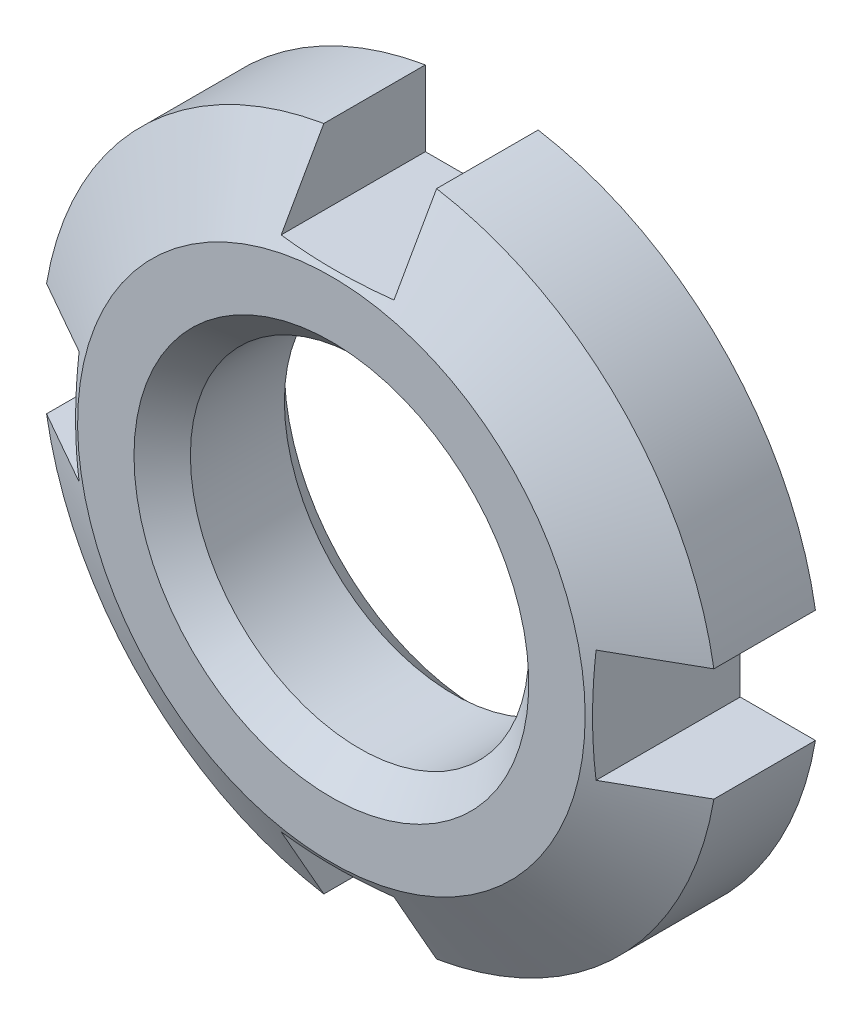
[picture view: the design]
ISO-10303-21;
HEADER;
FILE_DESCRIPTION(('STEP AP214'),'2;1');
FILE_NAME('part.step','',(''),(''),'','','');
FILE_SCHEMA(('AUTOMOTIVE_DESIGN { 1 0 10303 214 1 1 1 1 }'));
ENDSEC;
DATA;
#1=APPLICATION_CONTEXT('core data for automotive mechanical design processes');
#2=APPLICATION_PROTOCOL_DEFINITION('international standard','automotive_design',2000,#1);
#3=PRODUCT_CONTEXT('',#1,'mechanical');
#4=PRODUCT('Part','Part','',(#3));
#5=PRODUCT_RELATED_PRODUCT_CATEGORY('part','',(#4));
#6=PRODUCT_DEFINITION_FORMATION('','',#4);
#7=PRODUCT_DEFINITION_CONTEXT('part definition',#1,'design');
#8=PRODUCT_DEFINITION('design','',#6,#7);
#9=PRODUCT_DEFINITION_SHAPE('','',#8);
#10=(LENGTH_UNIT() NAMED_UNIT(*) SI_UNIT(.MILLI.,.METRE.));
#11=(NAMED_UNIT(*) PLANE_ANGLE_UNIT() SI_UNIT($,.RADIAN.));
#12=(NAMED_UNIT(*) SI_UNIT($,.STERADIAN.) SOLID_ANGLE_UNIT());
#13=UNCERTAINTY_MEASURE_WITH_UNIT(LENGTH_MEASURE(1.E-05),#10,'distance_accuracy_value','');
#14=(GEOMETRIC_REPRESENTATION_CONTEXT(3) GLOBAL_UNCERTAINTY_ASSIGNED_CONTEXT((#13)) GLOBAL_UNIT_ASSIGNED_CONTEXT((#10,
#11,#12)) REPRESENTATION_CONTEXT('',''));
#15=CARTESIAN_POINT('',(0.,0.,0.));
#16=DIRECTION('',(0.,0.,1.));
#17=DIRECTION('',(1.,0.,0.));
#18=AXIS2_PLACEMENT_3D('',#15,#16,#17);
#19=CARTESIAN_POINT('',(-9.,0.,0.));
#20=DIRECTION('',(0.,0.,1.));
#21=DIRECTION('',(1.,0.,0.));
#22=AXIS2_PLACEMENT_3D('',#19,#20,#21);
#23=PLANE('',#22);
#24=CARTESIAN_POINT('',(0.,0.,0.));
#25=DIRECTION('',(0.,0.,1.));
#26=DIRECTION('',(1.,0.,0.));
#27=AXIS2_PLACEMENT_3D('',#24,#25,#26);
#28=CIRCLE('',#27,5.25);
#29=CARTESIAN_POINT('',(5.25,0.,0.));
#30=VERTEX_POINT('',#29);
#31=EDGE_CURVE('E275',#30,#30,#28,.T.);
#32=ORIENTED_EDGE('',*,*,#31,.T.);
#33=EDGE_LOOP('',(#32));
#34=FACE_BOUND('',#33,.T.);
#35=DIRECTION('',(1.,0.,0.));
#36=VECTOR('',#35,1.);
#37=CARTESIAN_POINT('',(-9.87411967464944,-1.4999999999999,0.));
#38=LINE('',#37,#36);
#39=CARTESIAN_POINT('',(-8.87411967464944,-1.49999999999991,0.));
#40=VERTEX_POINT('',#39);
#41=CARTESIAN_POINT('',(-6.87411967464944,-1.49999999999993,0.));
#42=VERTEX_POINT('',#41);
#43=EDGE_CURVE('E539',#40,#42,#38,.T.);
#44=ORIENTED_EDGE('',*,*,#43,.T.);
#45=DIRECTION('',(0.,1.,0.));
#46=VECTOR('',#45,1.);
#47=CARTESIAN_POINT('',(-6.87411967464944,-1.49999999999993,0.));
#48=LINE('',#47,#46);
#49=CARTESIAN_POINT('',(-6.87411967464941,1.50000000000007,0.));
#50=VERTEX_POINT('',#49);
#51=EDGE_CURVE('E165',#42,#50,#48,.T.);
#52=ORIENTED_EDGE('',*,*,#51,.T.);
#53=DIRECTION('',(-1.,0.,0.));
#54=VECTOR('',#53,1.);
#55=CARTESIAN_POINT('',(-9.87411967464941,1.5000000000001,0.));
#56=LINE('',#55,#54);
#57=CARTESIAN_POINT('',(-8.87411967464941,1.50000000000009,0.));
#58=VERTEX_POINT('',#57);
#59=EDGE_CURVE('E151',#50,#58,#56,.T.);
#60=ORIENTED_EDGE('',*,*,#59,.T.);
#61=CARTESIAN_POINT('',(0.,0.,0.));
#62=DIRECTION('',(0.,0.,1.));
#63=DIRECTION('',(1.,0.,0.));
#64=AXIS2_PLACEMENT_3D('',#61,#62,#63);
#65=CIRCLE('',#64,9.);
#66=CARTESIAN_POINT('',(-1.5,8.87411967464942,0.));
#67=VERTEX_POINT('',#66);
#68=EDGE_CURVE('E164',#67,#58,#65,.T.);
#69=ORIENTED_EDGE('',*,*,#68,.F.);
#70=DIRECTION('',(0.,-1.,0.));
#71=VECTOR('',#70,1.);
#72=CARTESIAN_POINT('',(-1.5,9.87411967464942,0.));
#73=LINE('',#72,#71);
#74=CARTESIAN_POINT('',(-1.5,6.87411967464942,0.));
#75=VERTEX_POINT('',#74);
#76=EDGE_CURVE('E213',#67,#75,#73,.T.);
#77=ORIENTED_EDGE('',*,*,#76,.T.);
#78=DIRECTION('',(1.,0.,0.));
#79=VECTOR('',#78,1.);
#80=CARTESIAN_POINT('',(-1.5,6.87411967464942,0.));
#81=LINE('',#80,#79);
#82=CARTESIAN_POINT('',(1.5,6.87411967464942,0.));
#83=VERTEX_POINT('',#82);
#84=EDGE_CURVE('E210',#75,#83,#81,.T.);
#85=ORIENTED_EDGE('',*,*,#84,.T.);
#86=DIRECTION('',(0.,1.,0.));
#87=VECTOR('',#86,1.);
#88=CARTESIAN_POINT('',(1.5,9.87411967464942,0.));
#89=LINE('',#88,#87);
#90=CARTESIAN_POINT('',(1.5,8.87411967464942,0.));
#91=VERTEX_POINT('',#90);
#92=EDGE_CURVE('E207',#83,#91,#89,.T.);
#93=ORIENTED_EDGE('',*,*,#92,.T.);
#94=CARTESIAN_POINT('',(8.87411967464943,1.49999999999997,0.));
#95=VERTEX_POINT('',#94);
#96=EDGE_CURVE('E174',#95,#91,#65,.T.);
#97=ORIENTED_EDGE('',*,*,#96,.F.);
#98=DIRECTION('',(-1.,0.,0.));
#99=VECTOR('',#98,1.);
#100=CARTESIAN_POINT('',(9.87411967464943,1.49999999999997,0.));
#101=LINE('',#100,#99);
#102=CARTESIAN_POINT('',(6.87411967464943,1.49999999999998,0.));
#103=VERTEX_POINT('',#102);
#104=EDGE_CURVE('E215',#95,#103,#101,.T.);
#105=ORIENTED_EDGE('',*,*,#104,.T.);
#106=DIRECTION('',(0.,-1.,0.));
#107=VECTOR('',#106,1.);
#108=CARTESIAN_POINT('',(6.87411967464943,1.49999999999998,0.));
#109=LINE('',#108,#107);
#110=CARTESIAN_POINT('',(6.87411967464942,-1.50000000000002,0.));
#111=VERTEX_POINT('',#110);
#112=EDGE_CURVE('E251',#103,#111,#109,.T.);
#113=ORIENTED_EDGE('',*,*,#112,.T.);
#114=DIRECTION('',(1.,0.,0.));
#115=VECTOR('',#114,1.);
#116=CARTESIAN_POINT('',(9.87411967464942,-1.50000000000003,0.));
#117=LINE('',#116,#115);
#118=CARTESIAN_POINT('',(8.87411967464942,-1.50000000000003,0.));
#119=VERTEX_POINT('',#118);
#120=EDGE_CURVE('E581',#111,#119,#117,.T.);
#121=ORIENTED_EDGE('',*,*,#120,.T.);
#122=CARTESIAN_POINT('',(1.49999999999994,-8.87411967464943,0.));
#123=VERTEX_POINT('',#122);
#124=EDGE_CURVE('E178',#123,#119,#65,.T.);
#125=ORIENTED_EDGE('',*,*,#124,.F.);
#126=DIRECTION('',(0.,1.,0.));
#127=VECTOR('',#126,1.);
#128=CARTESIAN_POINT('',(1.49999999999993,-9.87411967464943,0.));
#129=LINE('',#128,#127);
#130=CARTESIAN_POINT('',(1.49999999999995,-6.87411967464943,0.));
#131=VERTEX_POINT('',#130);
#132=EDGE_CURVE('E573',#123,#131,#129,.T.);
#133=ORIENTED_EDGE('',*,*,#132,.T.);
#134=DIRECTION('',(-1.,0.,0.));
#135=VECTOR('',#134,1.);
#136=CARTESIAN_POINT('',(1.49999999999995,-6.87411967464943,0.));
#137=LINE('',#136,#135);
#138=CARTESIAN_POINT('',(-1.50000000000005,-6.87411967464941,0.));
#139=VERTEX_POINT('',#138);
#140=EDGE_CURVE('E591',#131,#139,#137,.T.);
#141=ORIENTED_EDGE('',*,*,#140,.T.);
#142=DIRECTION('',(0.,-1.,0.));
#143=VECTOR('',#142,1.);
#144=CARTESIAN_POINT('',(-1.50000000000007,-9.87411967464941,0.));
#145=LINE('',#144,#143);
#146=CARTESIAN_POINT('',(-1.50000000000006,-8.87411967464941,0.));
#147=VERTEX_POINT('',#146);
#148=EDGE_CURVE('E546',#139,#147,#145,.T.);
#149=ORIENTED_EDGE('',*,*,#148,.T.);
#150=EDGE_CURVE('E172',#40,#147,#65,.T.);
#151=ORIENTED_EDGE('',*,*,#150,.F.);
#152=EDGE_LOOP('',(#44,#52,#60,#69,#77,#85,#93,#97,#105,#113,#121,#125,#133,#141,#149,#151));
#153=FACE_BOUND('',#152,.T.);
#154=ADVANCED_FACE('F34',(#34,#153),#23,.F.);
#155=CARTESIAN_POINT('',(-6.75,0.,4.));
#156=DIRECTION('',(0.,0.,-1.));
#157=DIRECTION('',(-1.,0.,0.));
#158=AXIS2_PLACEMENT_3D('',#155,#156,#157);
#159=PLANE('',#158);
#160=CARTESIAN_POINT('',(0.,0.,4.));
#161=DIRECTION('',(0.,0.,-1.));
#162=DIRECTION('',(-1.,0.,0.));
#163=AXIS2_PLACEMENT_3D('',#160,#161,#162);
#164=CIRCLE('',#163,5.25);
#165=CARTESIAN_POINT('',(-5.25,0.,4.));
#166=VERTEX_POINT('',#165);
#167=EDGE_CURVE('E11',#166,#166,#164,.T.);
#168=ORIENTED_EDGE('',*,*,#167,.T.);
#169=EDGE_LOOP('',(#168));
#170=FACE_BOUND('',#169,.T.);
#171=CARTESIAN_POINT('',(0.,0.,4.));
#172=DIRECTION('',(0.,0.,1.));
#173=DIRECTION('',(1.,0.,0.));
#174=AXIS2_PLACEMENT_3D('',#171,#172,#173);
#175=CIRCLE('',#174,6.75);
#176=CARTESIAN_POINT('',(6.75,0.,4.));
#177=VERTEX_POINT('',#176);
#178=EDGE_CURVE('E192',#177,#177,#175,.T.);
#179=ORIENTED_EDGE('',*,*,#178,.T.);
#180=EDGE_LOOP('',(#179));
#181=FACE_BOUND('',#180,.T.);
#182=ADVANCED_FACE('F300',(#170,#181),#159,.F.);
#183=CARTESIAN_POINT('',(0.,0.,0.));
#184=DIRECTION('',(0.,0.,1.));
#185=DIRECTION('',(1.,0.,0.));
#186=AXIS2_PLACEMENT_3D('',#183,#184,#185);
#187=CYLINDRICAL_SURFACE('',#186,9.);
#188=DIRECTION('',(0.,0.,1.));
#189=VECTOR('',#188,1.);
#190=CARTESIAN_POINT('',(-8.87411967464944,-1.49999999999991,0.));
#191=LINE('',#190,#189);
#192=CARTESIAN_POINT('',(-8.87411967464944,-1.49999999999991,2.70096189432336));
#193=VERTEX_POINT('',#192);
#194=EDGE_CURVE('E540',#40,#193,#191,.T.);
#195=ORIENTED_EDGE('',*,*,#194,.F.);
#196=ORIENTED_EDGE('',*,*,#150,.T.);
#197=DIRECTION('',(0.,0.,1.));
#198=VECTOR('',#197,1.);
#199=CARTESIAN_POINT('',(-1.50000000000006,-8.87411967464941,0.));
#200=LINE('',#199,#198);
#201=CARTESIAN_POINT('',(-1.50000000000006,-8.87411967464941,2.70096189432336));
#202=VERTEX_POINT('',#201);
#203=EDGE_CURVE('E543',#202,#147,#200,.F.);
#204=ORIENTED_EDGE('',*,*,#203,.F.);
#205=CARTESIAN_POINT('',(0.,0.,2.70096189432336));
#206=DIRECTION('',(0.,0.,1.));
#207=DIRECTION('',(1.,0.,0.));
#208=AXIS2_PLACEMENT_3D('',#205,#206,#207);
#209=CIRCLE('',#208,9.);
#210=EDGE_CURVE('E186',#193,#202,#209,.T.);
#211=ORIENTED_EDGE('',*,*,#210,.F.);
#212=EDGE_LOOP('',(#195,#196,#204,#211));
#213=FACE_BOUND('',#212,.T.);
#214=ADVANCED_FACE('F302',(#213),#187,.T.);
#215=DIRECTION('',(0.,0.,1.));
#216=VECTOR('',#215,1.);
#217=CARTESIAN_POINT('',(-8.87411967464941,1.50000000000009,0.));
#218=LINE('',#217,#216);
#219=CARTESIAN_POINT('',(-8.87411967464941,1.50000000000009,2.70096189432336));
#220=VERTEX_POINT('',#219);
#221=EDGE_CURVE('E148',#220,#58,#218,.F.);
#222=ORIENTED_EDGE('',*,*,#221,.F.);
#223=CARTESIAN_POINT('',(-1.5,8.87411967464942,2.70096189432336));
#224=VERTEX_POINT('',#223);
#225=EDGE_CURVE('E180',#224,#220,#209,.T.);
#226=ORIENTED_EDGE('',*,*,#225,.F.);
#227=DIRECTION('',(0.,0.,1.));
#228=VECTOR('',#227,1.);
#229=CARTESIAN_POINT('',(-1.5,8.87411967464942,0.));
#230=LINE('',#229,#228);
#231=EDGE_CURVE('E170',#67,#224,#230,.T.);
#232=ORIENTED_EDGE('',*,*,#231,.F.);
#233=ORIENTED_EDGE('',*,*,#68,.T.);
#234=EDGE_LOOP('',(#222,#226,#232,#233));
#235=FACE_BOUND('',#234,.T.);
#236=ADVANCED_FACE('F169',(#235),#187,.T.);
#237=CARTESIAN_POINT('',(0.,0.,2.70096189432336));
#238=DIRECTION('',(0.,0.,-1.));
#239=DIRECTION('',(-1.,0.,0.));
#240=AXIS2_PLACEMENT_3D('',#237,#238,#239);
#241=CONICAL_SURFACE('',#240,9.,1.0471975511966);
#242=ORIENTED_EDGE('',*,*,#178,.F.);
#243=EDGE_LOOP('',(#242));
#244=FACE_BOUND('',#243,.T.);
#245=CARTESIAN_POINT('',(-12.0482242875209,-1.49999999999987,0.887366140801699));
#246=CARTESIAN_POINT('',(-11.6966393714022,-1.49999999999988,1.08879188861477));
#247=CARTESIAN_POINT('',(-11.345001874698,-1.49999999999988,1.29012601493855));
#248=CARTESIAN_POINT('',(-10.6415746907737,-1.49999999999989,1.69252518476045));
#249=CARTESIAN_POINT('',(-10.2897850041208,-1.49999999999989,1.89359022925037));
#250=CARTESIAN_POINT('',(-9.58601538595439,-1.4999999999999,2.29536027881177));
#251=CARTESIAN_POINT('',(-9.23403546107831,-1.4999999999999,2.49606529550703));
#252=CARTESIAN_POINT('',(-8.52979354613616,-1.49999999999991,2.89698358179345));
#253=CARTESIAN_POINT('',(-8.17753155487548,-1.49999999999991,3.09719684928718));
#254=CARTESIAN_POINT('',(-7.47258606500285,-1.49999999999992,3.49691980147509));
#255=CARTESIAN_POINT('',(-7.11990254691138,-1.49999999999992,3.69642945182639));
#256=CARTESIAN_POINT('',(-6.41393090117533,-1.49999999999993,4.09436975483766));
#257=CARTESIAN_POINT('',(-6.06064277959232,-1.49999999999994,4.29280041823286));
#258=CARTESIAN_POINT('',(-5.52995961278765,-1.49999999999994,4.58912088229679));
#259=CARTESIAN_POINT('',(-5.35293605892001,-1.49999999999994,4.68767565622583));
#260=CARTESIAN_POINT('',(-4.99855912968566,-1.49999999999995,4.88418867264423));
#261=CARTESIAN_POINT('',(-4.82120575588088,-1.49999999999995,4.98214691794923));
#262=CARTESIAN_POINT('',(-4.4660556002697,-1.49999999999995,5.17727253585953));
#263=CARTESIAN_POINT('',(-4.28825880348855,-1.49999999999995,5.27443988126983));
#264=CARTESIAN_POINT('',(-3.93203557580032,-1.49999999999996,5.46761959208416));
#265=CARTESIAN_POINT('',(-3.75360913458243,-1.49999999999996,5.56363193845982));
#266=CARTESIAN_POINT('',(-3.5747746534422,-1.49999999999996,5.65888482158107));
#267=B_SPLINE_CURVE_WITH_KNOTS('',3,(#245,#246,#247,#248,#249,#250,#251,#252,#253,#254,#255,
#256,#257,#258,#259,#260,#261,#262,#263,#264,#265,#266),.UNSPECIFIED.,.F.,.F.,(4,2,2,2,2,2,2,2,
2,2,4),(0.,1.21558990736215,2.4311753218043,3.64672075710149,4.86227136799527,6.07788050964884,
7.29347753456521,7.90130346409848,8.50912652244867,9.11697039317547,9.72482426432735),.UNSPECIFIED.);
#268=CARTESIAN_POINT('',(-6.87411967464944,-1.49999999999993,3.8349506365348));
#269=VERTEX_POINT('',#268);
#270=EDGE_CURVE('E532',#193,#269,#267,.T.);
#271=ORIENTED_EDGE('',*,*,#270,.F.);
#272=ORIENTED_EDGE('',*,*,#210,.T.);
#273=CARTESIAN_POINT('',(-1.50000000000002,-3.57477465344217,5.65888482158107));
#274=CARTESIAN_POINT('',(-1.50000000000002,-3.72761749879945,5.57748838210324));
#275=CARTESIAN_POINT('',(-1.50000000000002,-3.88015653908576,5.49552547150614));
#276=CARTESIAN_POINT('',(-1.50000000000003,-4.18475291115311,5.33071348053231));
#277=CARTESIAN_POINT('',(-1.50000000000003,-4.3368102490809,5.24786441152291));
#278=CARTESIAN_POINT('',(-1.50000000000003,-4.64056875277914,5.08152711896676));
#279=CARTESIAN_POINT('',(-1.50000000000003,-4.7922699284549,4.99803891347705));
#280=CARTESIAN_POINT('',(-1.50000000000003,-5.09539871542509,4.83056622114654));
#281=CARTESIAN_POINT('',(-1.50000000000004,-5.24682632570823,4.74658173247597));
#282=CARTESIAN_POINT('',(-1.50000000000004,-5.70077797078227,4.49406380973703));
#283=CARTESIAN_POINT('',(-1.50000000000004,-6.00298389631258,4.32495873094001));
#284=CARTESIAN_POINT('',(-1.50000000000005,-6.60685200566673,3.98577781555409));
#285=CARTESIAN_POINT('',(-1.50000000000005,-6.90851418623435,3.815701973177));
#286=CARTESIAN_POINT('',(-1.50000000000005,-7.31254193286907,3.58732547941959));
#287=CARTESIAN_POINT('',(-1.50000000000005,-7.41507371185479,3.52931868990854));
#288=CARTESIAN_POINT('',(-1.50000000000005,-7.62009847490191,3.41323585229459));
#289=CARTESIAN_POINT('',(-1.50000000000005,-7.72259145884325,3.3551598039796));
#290=CARTESIAN_POINT('',(-1.50000000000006,-8.17753998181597,3.09719293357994));
#291=CARTESIAN_POINT('',(-1.50000000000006,-8.5298098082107,2.89697457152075));
#292=CARTESIAN_POINT('',(-1.50000000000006,-9.2340693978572,2.49604572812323));
#293=CARTESIAN_POINT('',(-1.50000000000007,-9.58605916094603,2.29533524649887));
#294=CARTESIAN_POINT('',(-1.50000000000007,-10.2898305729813,1.89356425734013));
#295=CARTESIAN_POINT('',(-1.50000000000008,-10.6416122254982,1.6925037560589));
#296=CARTESIAN_POINT('',(-1.50000000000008,-11.3450215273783,1.29011472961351));
#297=CARTESIAN_POINT('',(-1.50000000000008,-11.6966491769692,1.08878620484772));
#298=CARTESIAN_POINT('',(-1.50000000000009,-12.0482242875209,0.887366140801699));
#299=B_SPLINE_CURVE_WITH_KNOTS('',3,(#273,#274,#275,#276,#277,#278,#279,#280,#281,#282,#283,
#284,#285,#286,#287,#288,#289,#290,#291,#292,#293,#294,#295,#296,#297,#298),.UNSPECIFIED.,.F.,
.F.,(4,2,2,2,2,2,2,2,2,2,2,2,4),(0.,0.519492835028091,1.03897901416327,1.55845057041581,
2.07792404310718,3.11682622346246,4.15573460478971,4.50914367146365,4.86255382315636,
6.07813233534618,7.29371155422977,8.509269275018,9.72482519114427),.UNSPECIFIED.);
#300=CARTESIAN_POINT('',(-1.50000000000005,-6.87411967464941,3.8349506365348));
#301=VERTEX_POINT('',#300);
#302=EDGE_CURVE('E551',#301,#202,#299,.T.);
#303=ORIENTED_EDGE('',*,*,#302,.F.);
#304=CARTESIAN_POINT('',(6.55885978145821,-6.87411967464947,2.41161333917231));
#305=CARTESIAN_POINT('',(6.33984463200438,-6.87411967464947,2.49887607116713));
#306=CARTESIAN_POINT('',(6.12004253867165,-6.87411967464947,2.58421702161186));
#307=CARTESIAN_POINT('',(5.67875239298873,-6.87411967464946,2.75015745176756));
#308=CARTESIAN_POINT('',(5.45726499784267,-6.87411967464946,2.83075868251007));
#309=CARTESIAN_POINT('',(5.01119995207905,-6.87411967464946,2.98678307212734));
#310=CARTESIAN_POINT('',(4.78661232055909,-6.87411967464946,3.06217785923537));
#311=CARTESIAN_POINT('',(4.33513790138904,-6.87411967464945,3.20628899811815));
#312=CARTESIAN_POINT('',(4.10824976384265,-6.87411967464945,3.27500114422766));
#313=CARTESIAN_POINT('',(3.65628850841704,-6.87411967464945,3.40326846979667));
#314=CARTESIAN_POINT('',(3.43125606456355,-6.87411967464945,3.46296603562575));
#315=CARTESIAN_POINT('',(2.97894419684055,-6.87411967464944,3.57331853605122));
#316=CARTESIAN_POINT('',(2.75166457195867,-6.87411967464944,3.62397265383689));
#317=CARTESIAN_POINT('',(2.29520223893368,-6.87411967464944,3.71478537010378));
#318=CARTESIAN_POINT('',(2.06602132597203,-6.87411967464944,3.75495291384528));
#319=CARTESIAN_POINT('',(1.60593171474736,-6.87411967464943,3.82349163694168));
#320=CARTESIAN_POINT('',(1.3750234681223,-6.87411967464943,3.85186579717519));
#321=CARTESIAN_POINT('',(0.986468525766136,-6.87411967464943,3.88868115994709));
#322=CARTESIAN_POINT('',(0.829145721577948,-6.87411967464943,3.9005982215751));
#323=CARTESIAN_POINT('',(0.514158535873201,-6.87411967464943,3.91828190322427));
#324=CARTESIAN_POINT('',(0.356494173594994,-6.87411967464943,3.92404886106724));
#325=CARTESIAN_POINT('',(0.0410198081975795,-6.87411967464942,3.92931284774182));
#326=CARTESIAN_POINT('',(-0.116790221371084,-6.87411967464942,3.92880831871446));
#327=CARTESIAN_POINT('',(-0.432259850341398,-6.87411967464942,3.92154340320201));
#328=CARTESIAN_POINT('',(-0.589919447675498,-6.87411967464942,3.91478293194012));
#329=CARTESIAN_POINT('',(-1.06354657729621,-6.87411967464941,3.88521008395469));
#330=CARTESIAN_POINT('',(-1.37897450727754,-6.87411967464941,3.85308764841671));
#331=CARTESIAN_POINT('',(-2.00660335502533,-6.87411967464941,3.76646010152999));
#332=CARTESIAN_POINT('',(-2.31880439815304,-6.87411967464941,3.71195586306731));
#333=CARTESIAN_POINT('',(-3.17085179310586,-6.8741196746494,3.53625507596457));
#334=CARTESIAN_POINT('',(-3.70669852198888,-6.8741196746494,3.39564334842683));
#335=CARTESIAN_POINT('',(-4.50141537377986,-6.87411967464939,3.15491392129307));
#336=CARTESIAN_POINT('',(-4.76507173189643,-6.87411967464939,3.06960166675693));
#337=CARTESIAN_POINT('',(-5.28961720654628,-6.87411967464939,2.89082717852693));
#338=CARTESIAN_POINT('',(-5.55050650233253,-6.87411967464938,2.797365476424));
#339=CARTESIAN_POINT('',(-6.06847952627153,-6.87411967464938,2.60431902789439));
#340=CARTESIAN_POINT('',(-6.32557583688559,-6.87411967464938,2.50476769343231));
#341=CARTESIAN_POINT('',(-6.83763997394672,-6.87411967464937,2.30030968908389));
#342=CARTESIAN_POINT('',(-7.09260769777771,-6.87411967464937,2.19540276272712));
#343=CARTESIAN_POINT('',(-7.5995555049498,-6.87411967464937,1.98168702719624));
#344=CARTESIAN_POINT('',(-7.85154384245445,-6.87411967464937,1.87289771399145));
#345=CARTESIAN_POINT('',(-8.35388494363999,-6.87411967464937,1.65172066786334));
#346=CARTESIAN_POINT('',(-8.60423798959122,-6.87411967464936,1.53933357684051));
#347=CARTESIAN_POINT('',(-8.85391912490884,-6.87411967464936,1.42549923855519));
#348=B_SPLINE_CURVE_WITH_KNOTS('',3,(#304,#305,#306,#307,#308,#309,#310,#311,#312,#313,#314,
#315,#316,#317,#318,#319,#320,#321,#322,#323,#324,#325,#326,#327,#328,#329,#330,#331,#332,#333,
#334,#335,#336,#337,#338,#339,#340,#341,#342,#343,#344,#345,#346,#347),.UNSPECIFIED.,.F.,.F.,(4,
2,2,2,2,2,2,2,2,2,2,2,2,2,2,2,2,2,2,2,2,4),(0.,0.707298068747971,1.41433317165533,
2.12495849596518,2.83602819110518,3.5343173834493,4.23266961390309,4.93042417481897,
5.62800226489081,6.10121365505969,6.57439905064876,7.04770198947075,7.52101134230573,
8.47118428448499,9.42132017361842,11.0805690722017,11.9118610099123,12.7430987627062,
13.5701261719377,14.3971932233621,15.2205703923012,16.0438014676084),.UNSPECIFIED.);
#349=CARTESIAN_POINT('',(1.49999999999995,-6.87411967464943,3.8349506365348));
#350=VERTEX_POINT('',#349);
#351=EDGE_CURVE('E57',#350,#301,#348,.T.);
#352=ORIENTED_EDGE('',*,*,#351,.F.);
#353=CARTESIAN_POINT('',(1.49999999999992,-12.0482242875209,0.887366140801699));
#354=CARTESIAN_POINT('',(1.49999999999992,-11.6966393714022,1.08879188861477));
#355=CARTESIAN_POINT('',(1.49999999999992,-11.345001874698,1.29012601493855));
#356=CARTESIAN_POINT('',(1.49999999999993,-10.6415746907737,1.69252518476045));
#357=CARTESIAN_POINT('',(1.49999999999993,-10.2897850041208,1.89359022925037));
#358=CARTESIAN_POINT('',(1.49999999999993,-9.58601538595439,2.29536027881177));
#359=CARTESIAN_POINT('',(1.49999999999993,-9.2340354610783,2.49606529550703));
#360=CARTESIAN_POINT('',(1.49999999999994,-8.52979354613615,2.89698358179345));
#361=CARTESIAN_POINT('',(1.49999999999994,-8.17753155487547,3.09719684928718));
#362=CARTESIAN_POINT('',(1.49999999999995,-7.47258606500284,3.49691980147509));
#363=CARTESIAN_POINT('',(1.49999999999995,-7.11990254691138,3.69642945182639));
#364=CARTESIAN_POINT('',(1.49999999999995,-6.41393090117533,4.09436975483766));
#365=CARTESIAN_POINT('',(1.49999999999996,-6.06064277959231,4.29280041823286));
#366=CARTESIAN_POINT('',(1.49999999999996,-5.52995961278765,4.58912088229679));
#367=CARTESIAN_POINT('',(1.49999999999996,-5.35293605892,4.68767565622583));
#368=CARTESIAN_POINT('',(1.49999999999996,-4.99855912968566,4.88418867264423));
#369=CARTESIAN_POINT('',(1.49999999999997,-4.82120575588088,4.98214691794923));
#370=CARTESIAN_POINT('',(1.49999999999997,-4.46605560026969,5.17727253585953));
#371=CARTESIAN_POINT('',(1.49999999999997,-4.28825880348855,5.27443988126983));
#372=CARTESIAN_POINT('',(1.49999999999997,-3.93203557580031,5.46761959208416));
#373=CARTESIAN_POINT('',(1.49999999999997,-3.75360913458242,5.56363193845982));
#374=CARTESIAN_POINT('',(1.49999999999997,-3.5747746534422,5.65888482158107));
#375=B_SPLINE_CURVE_WITH_KNOTS('',3,(#353,#354,#355,#356,#357,#358,#359,#360,#361,#362,#363,
#364,#365,#366,#367,#368,#369,#370,#371,#372,#373,#374),.UNSPECIFIED.,.F.,.F.,(4,2,2,2,2,2,2,2,
2,2,4),(0.,1.21558990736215,2.4311753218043,3.64672075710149,4.86227136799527,6.07788050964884,
7.29347753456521,7.90130346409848,8.50912652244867,9.11697039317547,9.72482426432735),.UNSPECIFIED.);
#376=CARTESIAN_POINT('',(1.49999999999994,-8.87411967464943,2.70096189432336));
#377=VERTEX_POINT('',#376);
#378=EDGE_CURVE('E566',#377,#350,#375,.T.);
#379=ORIENTED_EDGE('',*,*,#378,.F.);
#380=CARTESIAN_POINT('',(8.87411967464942,-1.50000000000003,2.70096189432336));
#381=VERTEX_POINT('',#380);
#382=EDGE_CURVE('E190',#377,#381,#209,.T.);
#383=ORIENTED_EDGE('',*,*,#382,.T.);
#384=CARTESIAN_POINT('',(3.57477465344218,-1.50000000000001,5.65888482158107));
#385=CARTESIAN_POINT('',(3.72761749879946,-1.50000000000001,5.57748838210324));
#386=CARTESIAN_POINT('',(3.88015653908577,-1.50000000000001,5.49552547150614));
#387=CARTESIAN_POINT('',(4.18475291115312,-1.50000000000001,5.33071348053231));
#388=CARTESIAN_POINT('',(4.33681024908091,-1.50000000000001,5.24786441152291));
#389=CARTESIAN_POINT('',(4.64056875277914,-1.50000000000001,5.08152711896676));
#390=CARTESIAN_POINT('',(4.7922699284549,-1.50000000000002,4.99803891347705));
#391=CARTESIAN_POINT('',(5.0953987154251,-1.50000000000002,4.83056622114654));
#392=CARTESIAN_POINT('',(5.24682632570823,-1.50000000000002,4.74658173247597));
#393=CARTESIAN_POINT('',(5.70077797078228,-1.50000000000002,4.49406380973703));
#394=CARTESIAN_POINT('',(6.00298389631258,-1.50000000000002,4.32495873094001));
#395=CARTESIAN_POINT('',(6.60685200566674,-1.50000000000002,3.98577781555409));
#396=CARTESIAN_POINT('',(6.90851418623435,-1.50000000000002,3.815701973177));
#397=CARTESIAN_POINT('',(7.31254193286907,-1.50000000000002,3.58732547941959));
#398=CARTESIAN_POINT('',(7.41507371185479,-1.50000000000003,3.52931868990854));
#399=CARTESIAN_POINT('',(7.62009847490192,-1.50000000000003,3.41323585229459));
#400=CARTESIAN_POINT('',(7.72259145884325,-1.50000000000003,3.3551598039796));
#401=CARTESIAN_POINT('',(8.17753998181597,-1.50000000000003,3.09719293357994));
#402=CARTESIAN_POINT('',(8.5298098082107,-1.50000000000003,2.89697457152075));
#403=CARTESIAN_POINT('',(9.23406939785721,-1.50000000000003,2.49604572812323));
#404=CARTESIAN_POINT('',(9.58605916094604,-1.50000000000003,2.29533524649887));
#405=CARTESIAN_POINT('',(10.2898305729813,-1.50000000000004,1.89356425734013));
#406=CARTESIAN_POINT('',(10.6416122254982,-1.50000000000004,1.6925037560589));
#407=CARTESIAN_POINT('',(11.3450215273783,-1.50000000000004,1.29011472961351));
#408=CARTESIAN_POINT('',(11.6966491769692,-1.50000000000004,1.08878620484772));
#409=CARTESIAN_POINT('',(12.0482242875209,-1.50000000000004,0.887366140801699));
#410=B_SPLINE_CURVE_WITH_KNOTS('',3,(#384,#385,#386,#387,#388,#389,#390,#391,#392,#393,#394,
#395,#396,#397,#398,#399,#400,#401,#402,#403,#404,#405,#406,#407,#408,#409),.UNSPECIFIED.,.F.,
.F.,(4,2,2,2,2,2,2,2,2,2,2,2,4),(0.,0.519492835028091,1.03897901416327,1.55845057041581,
2.07792404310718,3.11682622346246,4.15573460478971,4.50914367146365,4.86255382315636,
6.07813233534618,7.29371155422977,8.509269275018,9.72482519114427),.UNSPECIFIED.);
#411=CARTESIAN_POINT('',(6.87411967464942,-1.50000000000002,3.8349506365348));
#412=VERTEX_POINT('',#411);
#413=EDGE_CURVE('E252',#412,#381,#410,.T.);
#414=ORIENTED_EDGE('',*,*,#413,.F.);
#415=CARTESIAN_POINT('',(6.87411967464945,6.55885978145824,2.41161333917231));
#416=CARTESIAN_POINT('',(6.87411967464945,6.3398446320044,2.49887607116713));
#417=CARTESIAN_POINT('',(6.87411967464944,6.12004253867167,2.58421702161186));
#418=CARTESIAN_POINT('',(6.87411967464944,5.67875239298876,2.75015745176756));
#419=CARTESIAN_POINT('',(6.87411967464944,5.4572649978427,2.83075868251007));
#420=CARTESIAN_POINT('',(6.87411967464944,5.01119995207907,2.98678307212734));
#421=CARTESIAN_POINT('',(6.87411967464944,4.78661232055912,3.06217785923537));
#422=CARTESIAN_POINT('',(6.87411967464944,4.33513790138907,3.20628899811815));
#423=CARTESIAN_POINT('',(6.87411967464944,4.10824976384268,3.27500114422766));
#424=CARTESIAN_POINT('',(6.87411967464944,3.65628850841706,3.40326846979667));
#425=CARTESIAN_POINT('',(6.87411967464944,3.43125606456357,3.46296603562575));
#426=CARTESIAN_POINT('',(6.87411967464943,2.97894419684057,3.57331853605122));
#427=CARTESIAN_POINT('',(6.87411967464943,2.75166457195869,3.62397265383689));
#428=CARTESIAN_POINT('',(6.87411967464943,2.2952022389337,3.71478537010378));
#429=CARTESIAN_POINT('',(6.87411967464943,2.06602132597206,3.75495291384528));
#430=CARTESIAN_POINT('',(6.87411967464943,1.60593171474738,3.82349163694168));
#431=CARTESIAN_POINT('',(6.87411967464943,1.37502346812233,3.85186579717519));
#432=CARTESIAN_POINT('',(6.87411967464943,0.98646852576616,3.88868115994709));
#433=CARTESIAN_POINT('',(6.87411967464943,0.829145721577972,3.9005982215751));
#434=CARTESIAN_POINT('',(6.87411967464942,0.514158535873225,3.91828190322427));
#435=CARTESIAN_POINT('',(6.87411967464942,0.356494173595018,3.92404886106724));
#436=CARTESIAN_POINT('',(6.87411967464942,0.0410198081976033,3.92931284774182));
#437=CARTESIAN_POINT('',(6.87411967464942,-0.11679022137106,3.92880831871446));
#438=CARTESIAN_POINT('',(6.87411967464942,-0.432259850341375,3.92154340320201));
#439=CARTESIAN_POINT('',(6.87411967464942,-0.589919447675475,3.91478293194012));
#440=CARTESIAN_POINT('',(6.87411967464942,-1.06354657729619,3.88521008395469));
#441=CARTESIAN_POINT('',(6.87411967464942,-1.37897450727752,3.85308764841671));
#442=CARTESIAN_POINT('',(6.87411967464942,-2.00660335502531,3.76646010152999));
#443=CARTESIAN_POINT('',(6.87411967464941,-2.31880439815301,3.71195586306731));
#444=CARTESIAN_POINT('',(6.87411967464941,-3.17085179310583,3.53625507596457));
#445=CARTESIAN_POINT('',(6.87411967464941,-3.70669852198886,3.39564334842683));
#446=CARTESIAN_POINT('',(6.87411967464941,-4.50141537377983,3.15491392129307));
#447=CARTESIAN_POINT('',(6.87411967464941,-4.76507173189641,3.06960166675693));
#448=CARTESIAN_POINT('',(6.8741196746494,-5.28961720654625,2.89082717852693));
#449=CARTESIAN_POINT('',(6.8741196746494,-5.5505065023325,2.797365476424));
#450=CARTESIAN_POINT('',(6.8741196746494,-6.06847952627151,2.60431902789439));
#451=CARTESIAN_POINT('',(6.8741196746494,-6.32557583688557,2.50476769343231));
#452=CARTESIAN_POINT('',(6.8741196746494,-6.83763997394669,2.30030968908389));
#453=CARTESIAN_POINT('',(6.8741196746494,-7.09260769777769,2.19540276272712));
#454=CARTESIAN_POINT('',(6.8741196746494,-7.59955550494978,1.98168702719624));
#455=CARTESIAN_POINT('',(6.8741196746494,-7.85154384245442,1.87289771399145));
#456=CARTESIAN_POINT('',(6.87411967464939,-8.35388494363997,1.65172066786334));
#457=CARTESIAN_POINT('',(6.87411967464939,-8.6042379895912,1.53933357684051));
#458=CARTESIAN_POINT('',(6.87411967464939,-8.85391912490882,1.42549923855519));
#459=B_SPLINE_CURVE_WITH_KNOTS('',3,(#415,#416,#417,#418,#419,#420,#421,#422,#423,#424,#425,
#426,#427,#428,#429,#430,#431,#432,#433,#434,#435,#436,#437,#438,#439,#440,#441,#442,#443,#444,
#445,#446,#447,#448,#449,#450,#451,#452,#453,#454,#455,#456,#457,#458),.UNSPECIFIED.,.F.,.F.,(4,
2,2,2,2,2,2,2,2,2,2,2,2,2,2,2,2,2,2,2,2,4),(0.,0.707298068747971,1.41433317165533,
2.12495849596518,2.83602819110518,3.5343173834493,4.23266961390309,4.93042417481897,
5.62800226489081,6.10121365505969,6.57439905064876,7.04770198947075,7.52101134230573,
8.47118428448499,9.42132017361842,11.0805690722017,11.9118610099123,12.7430987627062,
13.5701261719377,14.3971932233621,15.2205703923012,16.0438014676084),.UNSPECIFIED.);
#460=CARTESIAN_POINT('',(6.87411967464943,1.49999999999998,3.8349506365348));
#461=VERTEX_POINT('',#460);
#462=EDGE_CURVE('E245',#461,#412,#459,.T.);
#463=ORIENTED_EDGE('',*,*,#462,.F.);
#464=CARTESIAN_POINT('',(12.0482242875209,1.49999999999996,0.887366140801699));
#465=CARTESIAN_POINT('',(11.6966393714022,1.49999999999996,1.08879188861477));
#466=CARTESIAN_POINT('',(11.345001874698,1.49999999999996,1.29012601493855));
#467=CARTESIAN_POINT('',(10.6415746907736,1.49999999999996,1.69252518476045));
#468=CARTESIAN_POINT('',(10.2897850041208,1.49999999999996,1.89359022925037));
#469=CARTESIAN_POINT('',(9.58601538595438,1.49999999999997,2.29536027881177));
#470=CARTESIAN_POINT('',(9.2340354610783,1.49999999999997,2.49606529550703));
#471=CARTESIAN_POINT('',(8.52979354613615,1.49999999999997,2.89698358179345));
#472=CARTESIAN_POINT('',(8.17753155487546,1.49999999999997,3.09719684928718));
#473=CARTESIAN_POINT('',(7.47258606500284,1.49999999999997,3.49691980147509));
#474=CARTESIAN_POINT('',(7.11990254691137,1.49999999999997,3.69642945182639));
#475=CARTESIAN_POINT('',(6.41393090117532,1.49999999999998,4.09436975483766));
#476=CARTESIAN_POINT('',(6.06064277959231,1.49999999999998,4.29280041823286));
#477=CARTESIAN_POINT('',(5.52995961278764,1.49999999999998,4.58912088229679));
#478=CARTESIAN_POINT('',(5.35293605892,1.49999999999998,4.68767565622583));
#479=CARTESIAN_POINT('',(4.99855912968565,1.49999999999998,4.88418867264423));
#480=CARTESIAN_POINT('',(4.82120575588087,1.49999999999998,4.98214691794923));
#481=CARTESIAN_POINT('',(4.46605560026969,1.49999999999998,5.17727253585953));
#482=CARTESIAN_POINT('',(4.28825880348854,1.49999999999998,5.27443988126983));
#483=CARTESIAN_POINT('',(3.93203557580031,1.49999999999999,5.46761959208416));
#484=CARTESIAN_POINT('',(3.75360913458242,1.49999999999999,5.56363193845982));
#485=CARTESIAN_POINT('',(3.57477465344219,1.49999999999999,5.65888482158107));
#486=B_SPLINE_CURVE_WITH_KNOTS('',3,(#464,#465,#466,#467,#468,#469,#470,#471,#472,#473,#474,
#475,#476,#477,#478,#479,#480,#481,#482,#483,#484,#485),.UNSPECIFIED.,.F.,.F.,(4,2,2,2,2,2,2,2,
2,2,4),(0.,1.21558990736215,2.4311753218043,3.64672075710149,4.86227136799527,6.07788050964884,
7.29347753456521,7.90130346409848,8.50912652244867,9.11697039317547,9.72482426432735),.UNSPECIFIED.);
#487=CARTESIAN_POINT('',(8.87411967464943,1.49999999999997,2.70096189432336));
#488=VERTEX_POINT('',#487);
#489=EDGE_CURVE('E218',#488,#461,#486,.T.);
#490=ORIENTED_EDGE('',*,*,#489,.F.);
#491=CARTESIAN_POINT('',(1.5,8.87411967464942,2.70096189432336));
#492=VERTEX_POINT('',#491);
#493=EDGE_CURVE('E187',#488,#492,#209,.T.);
#494=ORIENTED_EDGE('',*,*,#493,.T.);
#495=CARTESIAN_POINT('',(1.5,3.57477465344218,5.65888482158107));
#496=CARTESIAN_POINT('',(1.5,3.72761749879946,5.57748838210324));
#497=CARTESIAN_POINT('',(1.5,3.88015653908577,5.49552547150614));
#498=CARTESIAN_POINT('',(1.5,4.18475291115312,5.33071348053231));
#499=CARTESIAN_POINT('',(1.5,4.33681024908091,5.24786441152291));
#500=CARTESIAN_POINT('',(1.5,4.64056875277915,5.08152711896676));
#501=CARTESIAN_POINT('',(1.5,4.79226992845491,4.99803891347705));
#502=CARTESIAN_POINT('',(1.5,5.0953987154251,4.83056622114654));
#503=CARTESIAN_POINT('',(1.5,5.24682632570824,4.74658173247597));
#504=CARTESIAN_POINT('',(1.5,5.70077797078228,4.49406380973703));
#505=CARTESIAN_POINT('',(1.5,6.00298389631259,4.32495873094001));
#506=CARTESIAN_POINT('',(1.5,6.60685200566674,3.98577781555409));
#507=CARTESIAN_POINT('',(1.5,6.90851418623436,3.815701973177));
#508=CARTESIAN_POINT('',(1.5,7.31254193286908,3.58732547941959));
#509=CARTESIAN_POINT('',(1.5,7.4150737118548,3.52931868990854));
#510=CARTESIAN_POINT('',(1.5,7.62009847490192,3.41323585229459));
#511=CARTESIAN_POINT('',(1.5,7.72259145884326,3.3551598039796));
#512=CARTESIAN_POINT('',(1.5,8.17753998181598,3.09719293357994));
#513=CARTESIAN_POINT('',(1.5,8.52980980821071,2.89697457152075));
#514=CARTESIAN_POINT('',(1.5,9.23406939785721,2.49604572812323));
#515=CARTESIAN_POINT('',(1.5,9.58605916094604,2.29533524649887));
#516=CARTESIAN_POINT('',(1.5,10.2898305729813,1.89356425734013));
#517=CARTESIAN_POINT('',(1.5,10.6416122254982,1.6925037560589));
#518=CARTESIAN_POINT('',(1.5,11.3450215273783,1.29011472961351));
#519=CARTESIAN_POINT('',(1.5,11.6966491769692,1.08878620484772));
#520=CARTESIAN_POINT('',(1.5,12.0482242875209,0.887366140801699));
#521=B_SPLINE_CURVE_WITH_KNOTS('',3,(#495,#496,#497,#498,#499,#500,#501,#502,#503,#504,#505,
#506,#507,#508,#509,#510,#511,#512,#513,#514,#515,#516,#517,#518,#519,#520),.UNSPECIFIED.,.F.,
.F.,(4,2,2,2,2,2,2,2,2,2,2,2,4),(0.,0.519492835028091,1.03897901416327,1.55845057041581,
2.07792404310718,3.11682622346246,4.15573460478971,4.50914367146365,4.86255382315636,
6.07813233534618,7.29371155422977,8.509269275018,9.72482519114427),.UNSPECIFIED.);
#522=CARTESIAN_POINT('',(1.5,6.87411967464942,3.8349506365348));
#523=VERTEX_POINT('',#522);
#524=EDGE_CURVE('E171',#523,#492,#521,.T.);
#525=ORIENTED_EDGE('',*,*,#524,.F.);
#526=CARTESIAN_POINT('',(-6.55885978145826,6.87411967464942,2.41161333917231));
#527=CARTESIAN_POINT('',(-6.33984463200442,6.87411967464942,2.49887607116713));
#528=CARTESIAN_POINT('',(-6.1200425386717,6.87411967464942,2.58421702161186));
#529=CARTESIAN_POINT('',(-5.67875239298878,6.87411967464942,2.75015745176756));
#530=CARTESIAN_POINT('',(-5.45726499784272,6.87411967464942,2.83075868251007));
#531=CARTESIAN_POINT('',(-5.0111999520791,6.87411967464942,2.98678307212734));
#532=CARTESIAN_POINT('',(-4.78661232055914,6.87411967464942,3.06217785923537));
#533=CARTESIAN_POINT('',(-4.33513790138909,6.87411967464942,3.20628899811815));
#534=CARTESIAN_POINT('',(-4.1082497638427,6.87411967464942,3.27500114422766));
#535=CARTESIAN_POINT('',(-3.65628850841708,6.87411967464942,3.40326846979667));
#536=CARTESIAN_POINT('',(-3.43125606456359,6.87411967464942,3.46296603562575));
#537=CARTESIAN_POINT('',(-2.97894419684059,6.87411967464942,3.57331853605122));
#538=CARTESIAN_POINT('',(-2.75166457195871,6.87411967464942,3.62397265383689));
#539=CARTESIAN_POINT('',(-2.29520223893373,6.87411967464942,3.71478537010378));
#540=CARTESIAN_POINT('',(-2.06602132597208,6.87411967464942,3.75495291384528));
#541=CARTESIAN_POINT('',(-1.60593171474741,6.87411967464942,3.82349163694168));
#542=CARTESIAN_POINT('',(-1.37502346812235,6.87411967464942,3.85186579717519));
#543=CARTESIAN_POINT('',(-0.986468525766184,6.87411967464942,3.88868115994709));
#544=CARTESIAN_POINT('',(-0.829145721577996,6.87411967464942,3.9005982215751));
#545=CARTESIAN_POINT('',(-0.514158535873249,6.87411967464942,3.91828190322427));
#546=CARTESIAN_POINT('',(-0.356494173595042,6.87411967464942,3.92404886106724));
#547=CARTESIAN_POINT('',(-0.0410198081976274,6.87411967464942,3.92931284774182));
#548=CARTESIAN_POINT('',(0.116790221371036,6.87411967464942,3.92880831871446));
#549=CARTESIAN_POINT('',(0.432259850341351,6.87411967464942,3.92154340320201));
#550=CARTESIAN_POINT('',(0.589919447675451,6.87411967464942,3.91478293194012));
#551=CARTESIAN_POINT('',(1.06354657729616,6.87411967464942,3.88521008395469));
#552=CARTESIAN_POINT('',(1.37897450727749,6.87411967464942,3.85308764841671));
#553=CARTESIAN_POINT('',(2.00660335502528,6.87411967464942,3.76646010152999));
#554=CARTESIAN_POINT('',(2.31880439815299,6.87411967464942,3.71195586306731));
#555=CARTESIAN_POINT('',(3.17085179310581,6.87411967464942,3.53625507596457));
#556=CARTESIAN_POINT('',(3.70669852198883,6.87411967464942,3.39564334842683));
#557=CARTESIAN_POINT('',(4.50141537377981,6.87411967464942,3.15491392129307));
#558=CARTESIAN_POINT('',(4.76507173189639,6.87411967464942,3.06960166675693));
#559=CARTESIAN_POINT('',(5.28961720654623,6.87411967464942,2.89082717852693));
#560=CARTESIAN_POINT('',(5.55050650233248,6.87411967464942,2.797365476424));
#561=CARTESIAN_POINT('',(6.06847952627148,6.87411967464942,2.60431902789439));
#562=CARTESIAN_POINT('',(6.32557583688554,6.87411967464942,2.50476769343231));
#563=CARTESIAN_POINT('',(6.83763997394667,6.87411967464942,2.30030968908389));
#564=CARTESIAN_POINT('',(7.09260769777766,6.87411967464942,2.19540276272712));
#565=CARTESIAN_POINT('',(7.59955550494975,6.87411967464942,1.98168702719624));
#566=CARTESIAN_POINT('',(7.8515438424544,6.87411967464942,1.87289771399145));
#567=CARTESIAN_POINT('',(8.35388494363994,6.87411967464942,1.65172066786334));
#568=CARTESIAN_POINT('',(8.60423798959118,6.87411967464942,1.53933357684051));
#569=CARTESIAN_POINT('',(8.85391912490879,6.87411967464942,1.42549923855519));
#570=B_SPLINE_CURVE_WITH_KNOTS('',3,(#526,#527,#528,#529,#530,#531,#532,#533,#534,#535,#536,
#537,#538,#539,#540,#541,#542,#543,#544,#545,#546,#547,#548,#549,#550,#551,#552,#553,#554,#555,
#556,#557,#558,#559,#560,#561,#562,#563,#564,#565,#566,#567,#568,#569),.UNSPECIFIED.,.F.,.F.,(4,
2,2,2,2,2,2,2,2,2,2,2,2,2,2,2,2,2,2,2,2,4),(0.,0.70729806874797,1.41433317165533,
2.12495849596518,2.83602819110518,3.5343173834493,4.23266961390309,4.93042417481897,
5.62800226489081,6.10121365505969,6.57439905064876,7.04770198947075,7.52101134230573,
8.47118428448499,9.42132017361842,11.0805690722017,11.9118610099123,12.7430987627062,
13.5701261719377,14.3971932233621,15.2205703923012,16.0438014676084),.UNSPECIFIED.);
#571=CARTESIAN_POINT('',(-1.5,6.87411967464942,3.8349506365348));
#572=VERTEX_POINT('',#571);
#573=EDGE_CURVE('E176',#572,#523,#570,.T.);
#574=ORIENTED_EDGE('',*,*,#573,.F.);
#575=CARTESIAN_POINT('',(-1.5,12.0482242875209,0.887366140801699));
#576=CARTESIAN_POINT('',(-1.5,11.6966393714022,1.08879188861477));
#577=CARTESIAN_POINT('',(-1.5,11.345001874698,1.29012601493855));
#578=CARTESIAN_POINT('',(-1.5,10.6415746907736,1.69252518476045));
#579=CARTESIAN_POINT('',(-1.5,10.2897850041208,1.89359022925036));
#580=CARTESIAN_POINT('',(-1.5,9.58601538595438,2.29536027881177));
#581=CARTESIAN_POINT('',(-1.5,9.2340354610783,2.49606529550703));
#582=CARTESIAN_POINT('',(-1.5,8.52979354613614,2.89698358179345));
#583=CARTESIAN_POINT('',(-1.5,8.17753155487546,3.09719684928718));
#584=CARTESIAN_POINT('',(-1.5,7.47258606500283,3.49691980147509));
#585=CARTESIAN_POINT('',(-1.5,7.11990254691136,3.69642945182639));
#586=CARTESIAN_POINT('',(-1.5,6.41393090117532,4.09436975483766));
#587=CARTESIAN_POINT('',(-1.5,6.0606427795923,4.29280041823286));
#588=CARTESIAN_POINT('',(-1.5,5.52995961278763,4.58912088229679));
#589=CARTESIAN_POINT('',(-1.5,5.35293605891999,4.68767565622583));
#590=CARTESIAN_POINT('',(-1.5,4.99855912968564,4.88418867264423));
#591=CARTESIAN_POINT('',(-1.5,4.82120575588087,4.98214691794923));
#592=CARTESIAN_POINT('',(-1.5,4.46605560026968,5.17727253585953));
#593=CARTESIAN_POINT('',(-1.5,4.28825880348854,5.27443988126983));
#594=CARTESIAN_POINT('',(-1.5,3.9320355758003,5.46761959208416));
#595=CARTESIAN_POINT('',(-1.5,3.75360913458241,5.56363193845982));
#596=CARTESIAN_POINT('',(-1.5,3.57477465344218,5.65888482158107));
#597=B_SPLINE_CURVE_WITH_KNOTS('',3,(#575,#576,#577,#578,#579,#580,#581,#582,#583,#584,#585,
#586,#587,#588,#589,#590,#591,#592,#593,#594,#595,#596),.UNSPECIFIED.,.F.,.F.,(4,2,2,2,2,2,2,2,
2,2,4),(0.,1.21558990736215,2.4311753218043,3.64672075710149,4.86227136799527,6.07788050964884,
7.29347753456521,7.90130346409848,8.50912652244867,9.11697039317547,9.72482426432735),.UNSPECIFIED.);
#598=EDGE_CURVE('E273',#224,#572,#597,.T.);
#599=ORIENTED_EDGE('',*,*,#598,.F.);
#600=ORIENTED_EDGE('',*,*,#225,.T.);
#601=CARTESIAN_POINT('',(-3.57477465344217,1.50000000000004,5.65888482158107));
#602=CARTESIAN_POINT('',(-3.72761749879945,1.50000000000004,5.57748838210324));
#603=CARTESIAN_POINT('',(-3.88015653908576,1.50000000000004,5.49552547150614));
#604=CARTESIAN_POINT('',(-4.18475291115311,1.50000000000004,5.33071348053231));
#605=CARTESIAN_POINT('',(-4.3368102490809,1.50000000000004,5.24786441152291));
#606=CARTESIAN_POINT('',(-4.64056875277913,1.50000000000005,5.08152711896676));
#607=CARTESIAN_POINT('',(-4.79226992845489,1.50000000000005,4.99803891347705));
#608=CARTESIAN_POINT('',(-5.09539871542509,1.50000000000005,4.83056622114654));
#609=CARTESIAN_POINT('',(-5.24682632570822,1.50000000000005,4.74658173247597));
#610=CARTESIAN_POINT('',(-5.70077797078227,1.50000000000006,4.49406380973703));
#611=CARTESIAN_POINT('',(-6.00298389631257,1.50000000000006,4.32495873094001));
#612=CARTESIAN_POINT('',(-6.60685200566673,1.50000000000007,3.98577781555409));
#613=CARTESIAN_POINT('',(-6.90851418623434,1.50000000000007,3.815701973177));
#614=CARTESIAN_POINT('',(-7.31254193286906,1.50000000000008,3.58732547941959));
#615=CARTESIAN_POINT('',(-7.41507371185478,1.50000000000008,3.52931868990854));
#616=CARTESIAN_POINT('',(-7.62009847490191,1.50000000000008,3.41323585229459));
#617=CARTESIAN_POINT('',(-7.72259145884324,1.50000000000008,3.3551598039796));
#618=CARTESIAN_POINT('',(-8.17753998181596,1.50000000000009,3.09719293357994));
#619=CARTESIAN_POINT('',(-8.52980980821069,1.50000000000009,2.89697457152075));
#620=CARTESIAN_POINT('',(-9.2340693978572,1.5000000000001,2.49604572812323));
#621=CARTESIAN_POINT('',(-9.58605916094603,1.5000000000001,2.29533524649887));
#622=CARTESIAN_POINT('',(-10.2898305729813,1.50000000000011,1.89356425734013));
#623=CARTESIAN_POINT('',(-10.6416122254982,1.50000000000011,1.6925037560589));
#624=CARTESIAN_POINT('',(-11.3450215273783,1.50000000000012,1.29011472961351));
#625=CARTESIAN_POINT('',(-11.6966491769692,1.50000000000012,1.08878620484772));
#626=CARTESIAN_POINT('',(-12.0482242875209,1.50000000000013,0.887366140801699));
#627=B_SPLINE_CURVE_WITH_KNOTS('',3,(#601,#602,#603,#604,#605,#606,#607,#608,#609,#610,#611,
#612,#613,#614,#615,#616,#617,#618,#619,#620,#621,#622,#623,#624,#625,#626),.UNSPECIFIED.,.F.,
.F.,(4,2,2,2,2,2,2,2,2,2,2,2,4),(0.,0.519492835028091,1.03897901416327,1.55845057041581,
2.07792404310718,3.11682622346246,4.15573460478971,4.50914367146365,4.86255382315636,
6.07813233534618,7.29371155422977,8.509269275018,9.72482519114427),.UNSPECIFIED.);
#628=CARTESIAN_POINT('',(-6.87411967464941,1.50000000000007,3.8349506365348));
#629=VERTEX_POINT('',#628);
#630=EDGE_CURVE('E153',#629,#220,#627,.T.);
#631=ORIENTED_EDGE('',*,*,#630,.F.);
#632=CARTESIAN_POINT('',(-6.87411967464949,-6.55885978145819,2.41161333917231));
#633=CARTESIAN_POINT('',(-6.87411967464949,-6.33984463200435,2.49887607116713));
#634=CARTESIAN_POINT('',(-6.87411967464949,-6.12004253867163,2.58421702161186));
#635=CARTESIAN_POINT('',(-6.87411967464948,-5.67875239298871,2.75015745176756));
#636=CARTESIAN_POINT('',(-6.87411967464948,-5.45726499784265,2.83075868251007));
#637=CARTESIAN_POINT('',(-6.87411967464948,-5.01119995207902,2.98678307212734));
#638=CARTESIAN_POINT('',(-6.87411967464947,-4.78661232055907,3.06217785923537));
#639=CARTESIAN_POINT('',(-6.87411967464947,-4.33513790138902,3.20628899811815));
#640=CARTESIAN_POINT('',(-6.87411967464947,-4.10824976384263,3.27500114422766));
#641=CARTESIAN_POINT('',(-6.87411967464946,-3.65628850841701,3.40326846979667));
#642=CARTESIAN_POINT('',(-6.87411967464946,-3.43125606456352,3.46296603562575));
#643=CARTESIAN_POINT('',(-6.87411967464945,-2.97894419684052,3.57331853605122));
#644=CARTESIAN_POINT('',(-6.87411967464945,-2.75166457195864,3.62397265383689));
#645=CARTESIAN_POINT('',(-6.87411967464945,-2.29520223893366,3.71478537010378));
#646=CARTESIAN_POINT('',(-6.87411967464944,-2.06602132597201,3.75495291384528));
#647=CARTESIAN_POINT('',(-6.87411967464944,-1.60593171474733,3.82349163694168));
#648=CARTESIAN_POINT('',(-6.87411967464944,-1.37502346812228,3.85186579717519));
#649=CARTESIAN_POINT('',(-6.87411967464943,-0.986468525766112,3.88868115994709));
#650=CARTESIAN_POINT('',(-6.87411967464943,-0.829145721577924,3.9005982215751));
#651=CARTESIAN_POINT('',(-6.87411967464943,-0.514158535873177,3.91828190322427));
#652=CARTESIAN_POINT('',(-6.87411967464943,-0.35649417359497,3.92404886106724));
#653=CARTESIAN_POINT('',(-6.87411967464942,-0.0410198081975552,3.92931284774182));
#654=CARTESIAN_POINT('',(-6.87411967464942,0.116790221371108,3.92880831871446));
#655=CARTESIAN_POINT('',(-6.87411967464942,0.432259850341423,3.92154340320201));
#656=CARTESIAN_POINT('',(-6.87411967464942,0.589919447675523,3.91478293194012));
#657=CARTESIAN_POINT('',(-6.87411967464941,1.06354657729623,3.88521008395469));
#658=CARTESIAN_POINT('',(-6.87411967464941,1.37897450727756,3.85308764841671));
#659=CARTESIAN_POINT('',(-6.8741196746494,2.00660335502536,3.76646010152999));
#660=CARTESIAN_POINT('',(-6.8741196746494,2.31880439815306,3.71195586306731));
#661=CARTESIAN_POINT('',(-6.87411967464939,3.17085179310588,3.53625507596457));
#662=CARTESIAN_POINT('',(-6.87411967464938,3.7066985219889,3.39564334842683));
#663=CARTESIAN_POINT('',(-6.87411967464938,4.50141537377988,3.15491392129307));
#664=CARTESIAN_POINT('',(-6.87411967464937,4.76507173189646,3.06960166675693));
#665=CARTESIAN_POINT('',(-6.87411967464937,5.2896172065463,2.89082717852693));
#666=CARTESIAN_POINT('',(-6.87411967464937,5.55050650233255,2.797365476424));
#667=CARTESIAN_POINT('',(-6.87411967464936,6.06847952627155,2.60431902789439));
#668=CARTESIAN_POINT('',(-6.87411967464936,6.32557583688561,2.50476769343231));
#669=CARTESIAN_POINT('',(-6.87411967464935,6.83763997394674,2.30030968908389));
#670=CARTESIAN_POINT('',(-6.87411967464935,7.09260769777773,2.19540276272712));
#671=CARTESIAN_POINT('',(-6.87411967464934,7.59955550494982,1.98168702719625));
#672=CARTESIAN_POINT('',(-6.87411967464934,7.85154384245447,1.87289771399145));
#673=CARTESIAN_POINT('',(-6.87411967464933,8.35388494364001,1.65172066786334));
#674=CARTESIAN_POINT('',(-6.87411967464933,8.60423798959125,1.53933357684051));
#675=CARTESIAN_POINT('',(-6.87411967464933,8.85391912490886,1.42549923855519));
#676=B_SPLINE_CURVE_WITH_KNOTS('',3,(#632,#633,#634,#635,#636,#637,#638,#639,#640,#641,#642,
#643,#644,#645,#646,#647,#648,#649,#650,#651,#652,#653,#654,#655,#656,#657,#658,#659,#660,#661,
#662,#663,#664,#665,#666,#667,#668,#669,#670,#671,#672,#673,#674,#675),.UNSPECIFIED.,.F.,.F.,(4,
2,2,2,2,2,2,2,2,2,2,2,2,2,2,2,2,2,2,2,2,4),(0.,0.707298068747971,1.41433317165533,
2.12495849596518,2.83602819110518,3.5343173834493,4.23266961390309,4.93042417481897,
5.62800226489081,6.10121365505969,6.57439905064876,7.04770198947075,7.52101134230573,
8.47118428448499,9.42132017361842,11.0805690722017,11.9118610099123,12.7430987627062,
13.5701261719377,14.3971932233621,15.2205703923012,16.0438014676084),.UNSPECIFIED.);
#677=EDGE_CURVE('E49',#269,#629,#676,.T.);
#678=ORIENTED_EDGE('',*,*,#677,.F.);
#679=EDGE_LOOP('',(#271,#272,#303,#352,#379,#383,#414,#463,#490,#494,#525,#574,#599,#600,#631,#678));
#680=FACE_BOUND('',#679,.T.);
#681=ADVANCED_FACE('F262',(#244,#680),#241,.T.);
#682=DIRECTION('',(0.,0.,1.));
#683=VECTOR('',#682,1.);
#684=CARTESIAN_POINT('',(1.49999999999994,-8.87411967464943,0.));
#685=LINE('',#684,#683);
#686=EDGE_CURVE('E574',#123,#377,#685,.T.);
#687=ORIENTED_EDGE('',*,*,#686,.F.);
#688=ORIENTED_EDGE('',*,*,#124,.T.);
#689=DIRECTION('',(0.,0.,1.));
#690=VECTOR('',#689,1.);
#691=CARTESIAN_POINT('',(8.87411967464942,-1.50000000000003,0.));
#692=LINE('',#691,#690);
#693=EDGE_CURVE('E578',#381,#119,#692,.F.);
#694=ORIENTED_EDGE('',*,*,#693,.F.);
#695=ORIENTED_EDGE('',*,*,#382,.F.);
#696=EDGE_LOOP('',(#687,#688,#694,#695));
#697=FACE_BOUND('',#696,.T.);
#698=ADVANCED_FACE('F335',(#697),#187,.T.);
#699=DIRECTION('',(0.,0.,1.));
#700=VECTOR('',#699,1.);
#701=CARTESIAN_POINT('',(8.87411967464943,1.49999999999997,0.));
#702=LINE('',#701,#700);
#703=EDGE_CURVE('E226',#95,#488,#702,.T.);
#704=ORIENTED_EDGE('',*,*,#703,.F.);
#705=ORIENTED_EDGE('',*,*,#96,.T.);
#706=DIRECTION('',(0.,0.,1.));
#707=VECTOR('',#706,1.);
#708=CARTESIAN_POINT('',(1.5,8.87411967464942,0.));
#709=LINE('',#708,#707);
#710=EDGE_CURVE('E199',#492,#91,#709,.F.);
#711=ORIENTED_EDGE('',*,*,#710,.F.);
#712=ORIENTED_EDGE('',*,*,#493,.F.);
#713=EDGE_LOOP('',(#704,#705,#711,#712));
#714=FACE_BOUND('',#713,.T.);
#715=ADVANCED_FACE('F264',(#714),#187,.T.);
#716=CARTESIAN_POINT('',(-1.5,9.87411967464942,4.));
#717=DIRECTION('',(1.,0.,0.));
#718=DIRECTION('',(0.,1.,0.));
#719=AXIS2_PLACEMENT_3D('',#716,#717,#718);
#720=PLANE('',#719);
#721=ORIENTED_EDGE('',*,*,#231,.T.);
#722=ORIENTED_EDGE('',*,*,#598,.T.);
#723=DIRECTION('',(0.,0.,-1.));
#724=VECTOR('',#723,1.);
#725=CARTESIAN_POINT('',(-1.5,6.87411967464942,4.));
#726=LINE('',#725,#724);
#727=EDGE_CURVE('E203',#572,#75,#726,.T.);
#728=ORIENTED_EDGE('',*,*,#727,.T.);
#729=ORIENTED_EDGE('',*,*,#76,.F.);
#730=EDGE_LOOP('',(#721,#722,#728,#729));
#731=FACE_BOUND('',#730,.T.);
#732=ADVANCED_FACE('F295',(#731),#720,.T.);
#733=CARTESIAN_POINT('',(-1.5,6.87411967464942,4.));
#734=DIRECTION('',(0.,1.,0.));
#735=DIRECTION('',(0.,0.,1.));
#736=AXIS2_PLACEMENT_3D('',#733,#734,#735);
#737=PLANE('',#736);
#738=ORIENTED_EDGE('',*,*,#573,.T.);
#739=DIRECTION('',(0.,0.,-1.));
#740=VECTOR('',#739,1.);
#741=CARTESIAN_POINT('',(1.5,6.87411967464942,4.));
#742=LINE('',#741,#740);
#743=EDGE_CURVE('E205',#523,#83,#742,.T.);
#744=ORIENTED_EDGE('',*,*,#743,.T.);
#745=ORIENTED_EDGE('',*,*,#84,.F.);
#746=ORIENTED_EDGE('',*,*,#727,.F.);
#747=EDGE_LOOP('',(#738,#744,#745,#746));
#748=FACE_BOUND('',#747,.T.);
#749=ADVANCED_FACE('F271',(#748),#737,.T.);
#750=CARTESIAN_POINT('',(1.5,9.87411967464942,4.));
#751=DIRECTION('',(-1.,0.,0.));
#752=DIRECTION('',(0.,-1.,0.));
#753=AXIS2_PLACEMENT_3D('',#750,#751,#752);
#754=PLANE('',#753);
#755=ORIENTED_EDGE('',*,*,#710,.T.);
#756=ORIENTED_EDGE('',*,*,#92,.F.);
#757=ORIENTED_EDGE('',*,*,#743,.F.);
#758=ORIENTED_EDGE('',*,*,#524,.T.);
#759=EDGE_LOOP('',(#755,#756,#757,#758));
#760=FACE_BOUND('',#759,.T.);
#761=ADVANCED_FACE('F235',(#760),#754,.T.);
#762=CARTESIAN_POINT('',(9.87411967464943,1.49999999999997,4.));
#763=DIRECTION('',(0.,-1.,0.));
#764=DIRECTION('',(1.,0.,0.));
#765=AXIS2_PLACEMENT_3D('',#762,#763,#764);
#766=PLANE('',#765);
#767=ORIENTED_EDGE('',*,*,#703,.T.);
#768=ORIENTED_EDGE('',*,*,#489,.T.);
#769=DIRECTION('',(0.,0.,-1.));
#770=VECTOR('',#769,1.);
#771=CARTESIAN_POINT('',(6.87411967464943,1.49999999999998,4.));
#772=LINE('',#771,#770);
#773=EDGE_CURVE('E258',#461,#103,#772,.T.);
#774=ORIENTED_EDGE('',*,*,#773,.T.);
#775=ORIENTED_EDGE('',*,*,#104,.F.);
#776=EDGE_LOOP('',(#767,#768,#774,#775));
#777=FACE_BOUND('',#776,.T.);
#778=ADVANCED_FACE('F230',(#777),#766,.T.);
#779=CARTESIAN_POINT('',(6.87411967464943,1.49999999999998,4.));
#780=DIRECTION('',(1.,0.,0.));
#781=DIRECTION('',(0.,0.,1.));
#782=AXIS2_PLACEMENT_3D('',#779,#780,#781);
#783=PLANE('',#782);
#784=ORIENTED_EDGE('',*,*,#462,.T.);
#785=DIRECTION('',(0.,0.,-1.));
#786=VECTOR('',#785,1.);
#787=CARTESIAN_POINT('',(6.87411967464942,-1.50000000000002,4.));
#788=LINE('',#787,#786);
#789=EDGE_CURVE('E583',#412,#111,#788,.T.);
#790=ORIENTED_EDGE('',*,*,#789,.T.);
#791=ORIENTED_EDGE('',*,*,#112,.F.);
#792=ORIENTED_EDGE('',*,*,#773,.F.);
#793=EDGE_LOOP('',(#784,#790,#791,#792));
#794=FACE_BOUND('',#793,.T.);
#795=ADVANCED_FACE('F234',(#794),#783,.T.);
#796=CARTESIAN_POINT('',(9.87411967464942,-1.50000000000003,4.));
#797=DIRECTION('',(0.,1.,0.));
#798=DIRECTION('',(-1.,0.,0.));
#799=AXIS2_PLACEMENT_3D('',#796,#797,#798);
#800=PLANE('',#799);
#801=ORIENTED_EDGE('',*,*,#693,.T.);
#802=ORIENTED_EDGE('',*,*,#120,.F.);
#803=ORIENTED_EDGE('',*,*,#789,.F.);
#804=ORIENTED_EDGE('',*,*,#413,.T.);
#805=EDGE_LOOP('',(#801,#802,#803,#804));
#806=FACE_BOUND('',#805,.T.);
#807=ADVANCED_FACE('F240',(#806),#800,.T.);
#808=CARTESIAN_POINT('',(1.49999999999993,-9.87411967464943,4.));
#809=DIRECTION('',(-1.,0.,0.));
#810=DIRECTION('',(0.,-1.,0.));
#811=AXIS2_PLACEMENT_3D('',#808,#809,#810);
#812=PLANE('',#811);
#813=ORIENTED_EDGE('',*,*,#686,.T.);
#814=ORIENTED_EDGE('',*,*,#378,.T.);
#815=DIRECTION('',(0.,0.,-1.));
#816=VECTOR('',#815,1.);
#817=CARTESIAN_POINT('',(1.49999999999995,-6.87411967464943,4.));
#818=LINE('',#817,#816);
#819=EDGE_CURVE('E594',#350,#131,#818,.T.);
#820=ORIENTED_EDGE('',*,*,#819,.T.);
#821=ORIENTED_EDGE('',*,*,#132,.F.);
#822=EDGE_LOOP('',(#813,#814,#820,#821));
#823=FACE_BOUND('',#822,.T.);
#824=ADVANCED_FACE('F391',(#823),#812,.T.);
#825=CARTESIAN_POINT('',(1.49999999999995,-6.87411967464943,4.));
#826=DIRECTION('',(0.,-1.,0.));
#827=DIRECTION('',(0.,0.,1.));
#828=AXIS2_PLACEMENT_3D('',#825,#826,#827);
#829=PLANE('',#828);
#830=ORIENTED_EDGE('',*,*,#351,.T.);
#831=DIRECTION('',(0.,0.,-1.));
#832=VECTOR('',#831,1.);
#833=CARTESIAN_POINT('',(-1.50000000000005,-6.87411967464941,4.));
#834=LINE('',#833,#832);
#835=EDGE_CURVE('E549',#301,#139,#834,.T.);
#836=ORIENTED_EDGE('',*,*,#835,.T.);
#837=ORIENTED_EDGE('',*,*,#140,.F.);
#838=ORIENTED_EDGE('',*,*,#819,.F.);
#839=EDGE_LOOP('',(#830,#836,#837,#838));
#840=FACE_BOUND('',#839,.T.);
#841=ADVANCED_FACE('F402',(#840),#829,.T.);
#842=CARTESIAN_POINT('',(-1.50000000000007,-9.87411967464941,4.));
#843=DIRECTION('',(1.,0.,0.));
#844=DIRECTION('',(0.,1.,0.));
#845=AXIS2_PLACEMENT_3D('',#842,#843,#844);
#846=PLANE('',#845);
#847=ORIENTED_EDGE('',*,*,#203,.T.);
#848=ORIENTED_EDGE('',*,*,#148,.F.);
#849=ORIENTED_EDGE('',*,*,#835,.F.);
#850=ORIENTED_EDGE('',*,*,#302,.T.);
#851=EDGE_LOOP('',(#847,#848,#849,#850));
#852=FACE_BOUND('',#851,.T.);
#853=ADVANCED_FACE('F412',(#852),#846,.T.);
#854=CARTESIAN_POINT('',(-9.87411967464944,-1.4999999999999,4.));
#855=DIRECTION('',(0.,1.,0.));
#856=DIRECTION('',(-1.,0.,0.));
#857=AXIS2_PLACEMENT_3D('',#854,#855,#856);
#858=PLANE('',#857);
#859=ORIENTED_EDGE('',*,*,#194,.T.);
#860=ORIENTED_EDGE('',*,*,#270,.T.);
#861=DIRECTION('',(0.,0.,-1.));
#862=VECTOR('',#861,1.);
#863=CARTESIAN_POINT('',(-6.87411967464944,-1.49999999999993,4.));
#864=LINE('',#863,#862);
#865=EDGE_CURVE('E601',#269,#42,#864,.T.);
#866=ORIENTED_EDGE('',*,*,#865,.T.);
#867=ORIENTED_EDGE('',*,*,#43,.F.);
#868=EDGE_LOOP('',(#859,#860,#866,#867));
#869=FACE_BOUND('',#868,.T.);
#870=ADVANCED_FACE('F421',(#869),#858,.T.);
#871=CARTESIAN_POINT('',(-6.87411967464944,-1.49999999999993,4.));
#872=DIRECTION('',(-1.,0.,0.));
#873=DIRECTION('',(0.,0.,1.));
#874=AXIS2_PLACEMENT_3D('',#871,#872,#873);
#875=PLANE('',#874);
#876=ORIENTED_EDGE('',*,*,#677,.T.);
#877=DIRECTION('',(0.,0.,-1.));
#878=VECTOR('',#877,1.);
#879=CARTESIAN_POINT('',(-6.87411967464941,1.50000000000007,4.));
#880=LINE('',#879,#878);
#881=EDGE_CURVE('E166',#629,#50,#880,.T.);
#882=ORIENTED_EDGE('',*,*,#881,.T.);
#883=ORIENTED_EDGE('',*,*,#51,.F.);
#884=ORIENTED_EDGE('',*,*,#865,.F.);
#885=EDGE_LOOP('',(#876,#882,#883,#884));
#886=FACE_BOUND('',#885,.T.);
#887=ADVANCED_FACE('F432',(#886),#875,.T.);
#888=CARTESIAN_POINT('',(-9.87411967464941,1.5000000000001,4.));
#889=DIRECTION('',(0.,-1.,0.));
#890=DIRECTION('',(1.,0.,0.));
#891=AXIS2_PLACEMENT_3D('',#888,#889,#890);
#892=PLANE('',#891);
#893=ORIENTED_EDGE('',*,*,#221,.T.);
#894=ORIENTED_EDGE('',*,*,#59,.F.);
#895=ORIENTED_EDGE('',*,*,#881,.F.);
#896=ORIENTED_EDGE('',*,*,#630,.T.);
#897=EDGE_LOOP('',(#893,#894,#895,#896));
#898=FACE_BOUND('',#897,.T.);
#899=ADVANCED_FACE('F150',(#898),#892,.T.);
#900=CARTESIAN_POINT('',(0.,0.,4.));
#901=DIRECTION('',(0.,0.,-1.));
#902=DIRECTION('',(-1.,0.,0.));
#903=AXIS2_PLACEMENT_3D('',#900,#901,#902);
#904=CYLINDRICAL_SURFACE('',#903,4.5);
#905=CARTESIAN_POINT('',(0.,0.,0.750000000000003));
#906=DIRECTION('',(0.,0.,1.));
#907=DIRECTION('',(1.,0.,0.));
#908=AXIS2_PLACEMENT_3D('',#905,#906,#907);
#909=CIRCLE('',#908,4.5);
#910=CARTESIAN_POINT('',(4.5,0.,0.750000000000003));
#911=VERTEX_POINT('',#910);
#912=EDGE_CURVE('E42',#911,#911,#909,.F.);
#913=ORIENTED_EDGE('',*,*,#912,.T.);
#914=EDGE_LOOP('',(#913));
#915=FACE_BOUND('',#914,.T.);
#916=CARTESIAN_POINT('',(0.,0.,3.25));
#917=DIRECTION('',(0.,0.,-1.));
#918=DIRECTION('',(-1.,0.,0.));
#919=AXIS2_PLACEMENT_3D('',#916,#917,#918);
#920=CIRCLE('',#919,4.5);
#921=CARTESIAN_POINT('',(-4.5,0.,3.25));
#922=VERTEX_POINT('',#921);
#923=EDGE_CURVE('E318',#922,#922,#920,.F.);
#924=ORIENTED_EDGE('',*,*,#923,.T.);
#925=EDGE_LOOP('',(#924));
#926=FACE_BOUND('',#925,.T.);
#927=ADVANCED_FACE('F326',(#915,#926),#904,.F.);
#928=CARTESIAN_POINT('',(0.,0.,0.));
#929=DIRECTION('',(0.,0.,-1.));
#930=DIRECTION('',(-1.,0.,0.));
#931=AXIS2_PLACEMENT_3D('',#928,#929,#930);
#932=CONICAL_SURFACE('',#931,5.25,0.785398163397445);
#933=ORIENTED_EDGE('',*,*,#912,.F.);
#934=EDGE_LOOP('',(#933));
#935=FACE_BOUND('',#934,.T.);
#936=ORIENTED_EDGE('',*,*,#31,.F.);
#937=EDGE_LOOP('',(#936));
#938=FACE_BOUND('',#937,.T.);
#939=ADVANCED_FACE('F315',(#935,#938),#932,.F.);
#940=CARTESIAN_POINT('',(0.,0.,3.25));
#941=DIRECTION('',(0.,0.,1.));
#942=DIRECTION('',(1.,0.,0.));
#943=AXIS2_PLACEMENT_3D('',#940,#941,#942);
#944=CONICAL_SURFACE('',#943,4.5,0.78539816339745);
#945=ORIENTED_EDGE('',*,*,#167,.F.);
#946=EDGE_LOOP('',(#945));
#947=FACE_BOUND('',#946,.T.);
#948=ORIENTED_EDGE('',*,*,#923,.F.);
#949=EDGE_LOOP('',(#948));
#950=FACE_BOUND('',#949,.T.);
#951=ADVANCED_FACE('F36',(#947,#950),#944,.F.);
#952=CLOSED_SHELL('',(#154,#182,#214,#236,#681,#698,#715,#732,#749,#761,#778,#795,#807,#824,
#841,#853,#870,#887,#899,#927,#939,#951));
#953=MANIFOLD_SOLID_BREP('B2',#952);
#954=ADVANCED_BREP_SHAPE_REPRESENTATION('',(#18,#953),#14);
#955=SHAPE_DEFINITION_REPRESENTATION(#9,#954);
ENDSEC;
END-ISO-10303-21;
